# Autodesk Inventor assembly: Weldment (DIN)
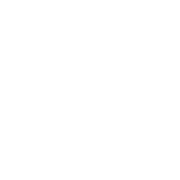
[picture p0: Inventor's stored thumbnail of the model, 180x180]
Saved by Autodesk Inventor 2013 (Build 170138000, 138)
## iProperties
Part Number: Weldment (DIN)
Document SubType Name: Weldment
Weld Material: Welded Aluminum-6061
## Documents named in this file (1)
- Z:\Vorlagen\Schweißkonstruktion.iam
